VERSION 5.7 ;
  NOWIREEXTENSIONATPIN ON ;
  DIVIDERCHAR "/" ;
  BUSBITCHARS "[]" ;
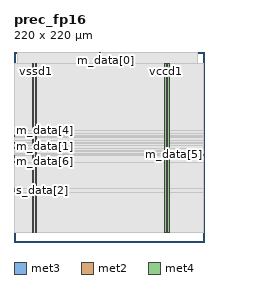
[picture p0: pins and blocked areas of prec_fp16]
MACRO prec_fp16
  CLASS BLOCK ;
  FOREIGN prec_fp16 ;
  ORIGIN 0.000 0.000 ;
  SIZE 220.000 BY 220.000 ;
  PIN clk
    DIRECTION INPUT ;
    USE SIGNAL ;
    ANTENNAGATEAREA 1.286700 ;
    ANTENNADIFFAREA 0.434700 ;
    PORT
      LAYER met3 ;
        RECT 0.000 126.520 0.600 127.120 ;
    END
  END clk
  PIN m_data[0]
    DIRECTION OUTPUT ;
    USE SIGNAL ;
    ANTENNADIFFAREA 0.795200 ;
    PORT
      LAYER met2 ;
        RECT 106.810 219.720 107.090 220.000 ;
    END
  END m_data[0]
  PIN m_data[1]
    DIRECTION OUTPUT ;
    USE SIGNAL ;
    ANTENNADIFFAREA 0.795200 ;
    PORT
      LAYER met3 ;
        RECT 0.000 110.200 0.600 110.800 ;
    END
  END m_data[1]
  PIN m_data[2]
    DIRECTION OUTPUT ;
    USE SIGNAL ;
    ANTENNADIFFAREA 0.795200 ;
    PORT
      LAYER met3 ;
        RECT 0.000 104.760 0.600 105.360 ;
    END
  END m_data[2]
  PIN m_data[3]
    DIRECTION OUTPUT ;
    USE SIGNAL ;
    ANTENNADIFFAREA 0.795200 ;
    PORT
      LAYER met2 ;
        RECT 99.450 219.720 99.730 220.000 ;
    END
  END m_data[3]
  PIN m_data[4]
    DIRECTION OUTPUT ;
    USE SIGNAL ;
    ANTENNADIFFAREA 0.795200 ;
    PORT
      LAYER met3 ;
        RECT 0.000 119.720 0.600 120.320 ;
    END
  END m_data[4]
  PIN m_data[5]
    DIRECTION OUTPUT ;
    USE SIGNAL ;
    ANTENNADIFFAREA 0.795200 ;
    PORT
      LAYER met3 ;
        RECT 219.400 100.680 220.000 101.280 ;
    END
  END m_data[5]
  PIN m_data[6]
    DIRECTION OUTPUT ;
    USE SIGNAL ;
    ANTENNADIFFAREA 0.795200 ;
    PORT
      LAYER met3 ;
        RECT 0.000 102.040 0.600 102.640 ;
    END
  END m_data[6]
  PIN m_data[7]
    DIRECTION OUTPUT ;
    USE SIGNAL ;
    ANTENNADIFFAREA 0.795200 ;
    PORT
      LAYER met2 ;
        RECT 110.490 219.720 110.770 220.000 ;
    END
  END m_data[7]
  PIN m_last
    DIRECTION OUTPUT ;
    USE SIGNAL ;
    ANTENNADIFFAREA 0.795200 ;
    PORT
      LAYER met3 ;
        RECT 0.000 127.880 0.600 128.480 ;
    END
  END m_last
  PIN m_ready
    DIRECTION INPUT ;
    USE SIGNAL ;
    ANTENNAGATEAREA 0.647700 ;
    ANTENNADIFFAREA 0.434700 ;
    PORT
      LAYER met3 ;
        RECT 0.000 114.280 0.600 114.880 ;
    END
  END m_ready
  PIN m_valid
    DIRECTION OUTPUT ;
    USE SIGNAL ;
    ANTENNADIFFAREA 0.795200 ;
    PORT
      LAYER met3 ;
        RECT 0.000 122.440 0.600 123.040 ;
    END
  END m_valid
  PIN rst
    DIRECTION INPUT ;
    USE SIGNAL ;
    ANTENNAGATEAREA 0.631200 ;
    ANTENNADIFFAREA 0.434700 ;
    PORT
      LAYER met3 ;
        RECT 0.000 118.360 0.600 118.960 ;
    END
  END rst
  PIN s_data[0]
    DIRECTION INPUT ;
    USE SIGNAL ;
    ANTENNAGATEAREA 0.647700 ;
    ANTENNADIFFAREA 0.434700 ;
    PORT
      LAYER met3 ;
        RECT 0.000 61.240 0.600 61.840 ;
    END
  END s_data[0]
  PIN s_data[1]
    DIRECTION INPUT ;
    USE SIGNAL ;
    ANTENNAGATEAREA 0.647700 ;
    ANTENNADIFFAREA 0.434700 ;
    PORT
      LAYER met3 ;
        RECT 0.000 57.160 0.600 57.760 ;
    END
  END s_data[1]
  PIN s_data[2]
    DIRECTION INPUT ;
    USE SIGNAL ;
    ANTENNAGATEAREA 0.647700 ;
    ANTENNADIFFAREA 0.434700 ;
    PORT
      LAYER met3 ;
        RECT 0.000 59.880 0.600 60.480 ;
    END
  END s_data[2]
  PIN s_data[3]
    DIRECTION INPUT ;
    USE SIGNAL ;
    ANTENNAGATEAREA 0.647700 ;
    ANTENNADIFFAREA 0.434700 ;
    PORT
      LAYER met3 ;
        RECT 0.000 58.520 0.600 59.120 ;
    END
  END s_data[3]
  PIN s_data[4]
    DIRECTION INPUT ;
    USE SIGNAL ;
    ANTENNAGATEAREA 0.647700 ;
    ANTENNADIFFAREA 0.434700 ;
    PORT
      LAYER met3 ;
        RECT 0.000 96.600 0.600 97.200 ;
    END
  END s_data[4]
  PIN s_data[5]
    DIRECTION INPUT ;
    USE SIGNAL ;
    ANTENNAGATEAREA 0.647700 ;
    ANTENNADIFFAREA 0.434700 ;
    PORT
      LAYER met3 ;
        RECT 0.000 92.520 0.600 93.120 ;
    END
  END s_data[5]
  PIN s_data[6]
    DIRECTION INPUT ;
    USE SIGNAL ;
    ANTENNAGATEAREA 0.647700 ;
    ANTENNADIFFAREA 0.434700 ;
    PORT
      LAYER met3 ;
        RECT 0.000 93.880 0.600 94.480 ;
    END
  END s_data[6]
  PIN s_data[7]
    DIRECTION INPUT ;
    USE SIGNAL ;
    ANTENNAGATEAREA 0.647700 ;
    ANTENNADIFFAREA 0.434700 ;
    PORT
      LAYER met3 ;
        RECT 0.000 95.240 0.600 95.840 ;
    END
  END s_data[7]
  PIN s_last
    DIRECTION INPUT ;
    USE SIGNAL ;
    ANTENNAGATEAREA 0.647700 ;
    ANTENNADIFFAREA 0.434700 ;
    PORT
      LAYER met3 ;
        RECT 0.000 99.320 0.600 99.920 ;
    END
  END s_last
  PIN s_ready
    DIRECTION OUTPUT ;
    USE SIGNAL ;
    ANTENNADIFFAREA 0.795200 ;
    PORT
      LAYER met3 ;
        RECT 0.000 108.840 0.600 109.440 ;
    END
  END s_ready
  PIN s_valid
    DIRECTION INPUT ;
    USE SIGNAL ;
    ANTENNAGATEAREA 0.647700 ;
    ANTENNADIFFAREA 0.434700 ;
    PORT
      LAYER met3 ;
        RECT 0.000 97.960 0.600 98.560 ;
    END
  END s_valid
  PIN vccd1
    DIRECTION INOUT ;
    USE POWER ;
    PORT
      LAYER met4 ;
        RECT 21.040 10.640 22.640 206.960 ;
    END
    PORT
      LAYER met4 ;
        RECT 174.640 10.640 176.240 206.960 ;
    END
  END vccd1
  PIN vssd1
    DIRECTION INOUT ;
    USE GROUND ;
    PORT
      LAYER met4 ;
        RECT 24.340 10.640 25.940 206.960 ;
    END
    PORT
      LAYER met4 ;
        RECT 177.940 10.640 179.540 206.960 ;
    END
  END vssd1
  OBS
      LAYER nwell ;
        RECT 5.330 10.795 214.550 206.805 ;
      LAYER li1 ;
        RECT 5.520 10.795 214.360 206.805 ;
      LAYER met1 ;
        RECT 3.750 10.640 214.360 206.960 ;
      LAYER met2 ;
        RECT 3.770 219.440 99.170 219.720 ;
        RECT 100.010 219.440 106.530 219.720 ;
        RECT 107.370 219.440 110.210 219.720 ;
        RECT 111.050 219.440 211.960 219.720 ;
        RECT 3.770 10.695 211.960 219.440 ;
      LAYER met3 ;
        RECT 0.600 128.880 219.400 206.885 ;
        RECT 1.000 126.120 219.400 128.880 ;
        RECT 0.600 123.440 219.400 126.120 ;
        RECT 1.000 122.040 219.400 123.440 ;
        RECT 0.600 120.720 219.400 122.040 ;
        RECT 1.000 117.960 219.400 120.720 ;
        RECT 0.600 115.280 219.400 117.960 ;
        RECT 1.000 113.880 219.400 115.280 ;
        RECT 0.600 111.200 219.400 113.880 ;
        RECT 1.000 108.440 219.400 111.200 ;
        RECT 0.600 105.760 219.400 108.440 ;
        RECT 1.000 104.360 219.400 105.760 ;
        RECT 0.600 103.040 219.400 104.360 ;
        RECT 1.000 101.680 219.400 103.040 ;
        RECT 1.000 101.640 219.000 101.680 ;
        RECT 0.600 100.320 219.000 101.640 ;
        RECT 1.000 100.280 219.000 100.320 ;
        RECT 1.000 92.120 219.400 100.280 ;
        RECT 0.600 62.240 219.400 92.120 ;
        RECT 1.000 56.760 219.400 62.240 ;
        RECT 0.600 10.715 219.400 56.760 ;
  END
END prec_fp16
END LIBRARY

